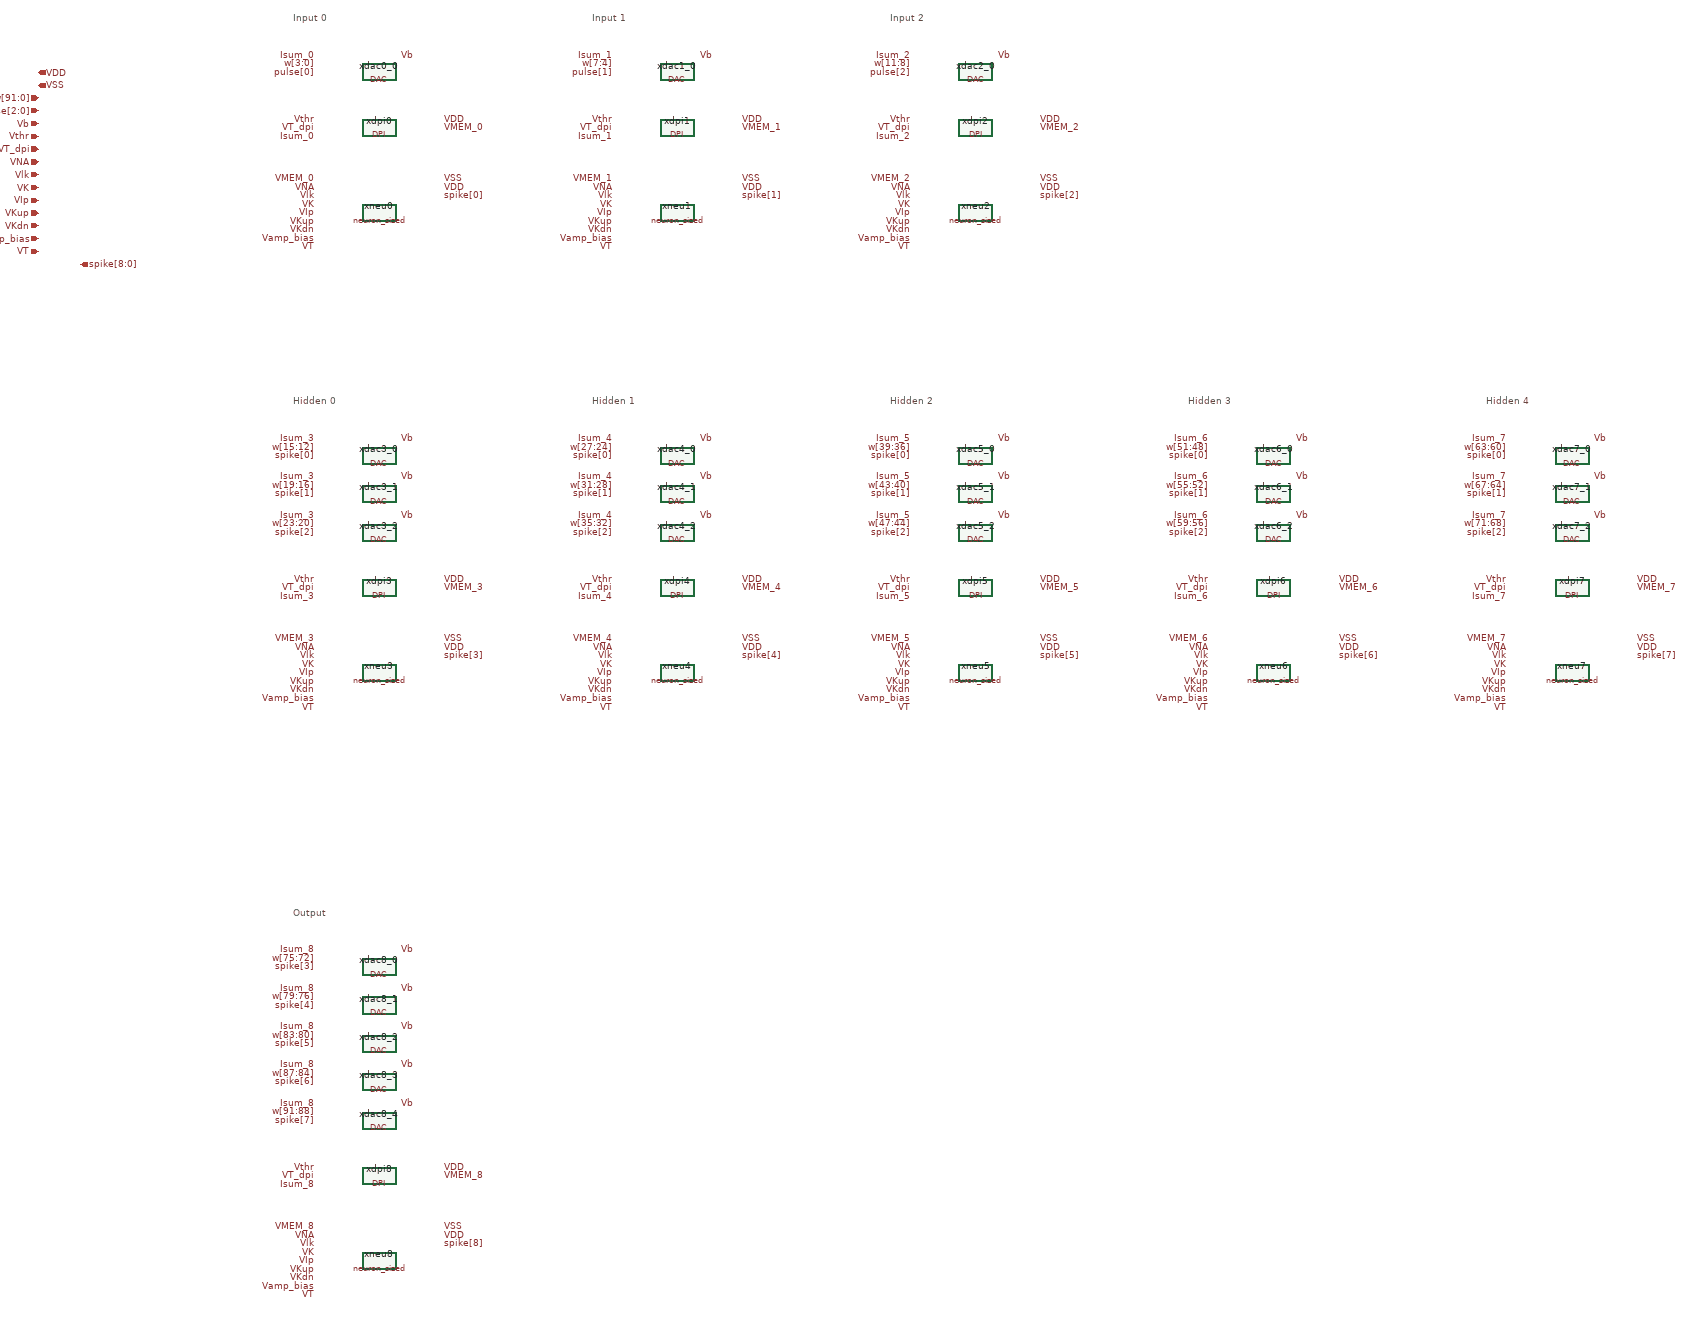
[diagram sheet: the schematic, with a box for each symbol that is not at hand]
v {xschem version=3.4.8RC file_version=1.3}
G {}
K {}
V {}
S {}
F {}
E {}
T {Input 0} 200 -1340 0 0 0.4 0.4 {}
C {DAC.sym} 400 -1200 0 0 {name=xdac0_0}
C {lab_pin.sym} 250 -1240 0 0 {name=l1 sig_type=std_logic lab=Isum_0}
C {lab_pin.sym} 450 -1240 0 1 {name=l2 sig_type=std_logic lab=Vb}
C {lab_pin.sym} 250 -1220 0 0 {name=l3 sig_type=std_logic lab=w[3:0]}
C {lab_pin.sym} 250 -1200 0 0 {name=l4 sig_type=std_logic lab=pulse[0]}
C {DPI.sym} 400 -1070 0 0 {name=xdpi0}
C {lab_pin.sym} 550 -1090 0 1 {name=l5 sig_type=std_logic lab=VDD}
C {lab_pin.sym} 250 -1090 0 0 {name=l6 sig_type=std_logic lab=Vthr}
C {lab_pin.sym} 550 -1070 0 1 {name=l7 sig_type=std_logic lab=VMEM_0}
C {lab_pin.sym} 250 -1050 0 0 {name=l8 sig_type=std_logic lab=Isum_0}
C {lab_pin.sym} 250 -1070 0 0 {name=l9 sig_type=std_logic lab=VT_dpi}
C {neuron_sized.sym} 400 -870 0 0 {name=xneu0}
C {lab_pin.sym} 550 -950 0 1 {name=l10 sig_type=std_logic lab=VSS}
C {lab_pin.sym} 550 -930 0 1 {name=l11 sig_type=std_logic lab=VDD}
C {lab_pin.sym} 550 -910 0 1 {name=l12 sig_type=std_logic lab=spike[0]}
C {lab_pin.sym} 250 -950 0 0 {name=l13 sig_type=std_logic lab=VMEM_0}
C {lab_pin.sym} 250 -930 0 0 {name=l14 sig_type=std_logic lab=VNA}
C {lab_pin.sym} 250 -910 0 0 {name=l15 sig_type=std_logic lab=Vlk}
C {lab_pin.sym} 250 -890 0 0 {name=l16 sig_type=std_logic lab=VK}
C {lab_pin.sym} 250 -870 0 0 {name=l17 sig_type=std_logic lab=VIp}
C {lab_pin.sym} 250 -850 0 0 {name=l18 sig_type=std_logic lab=VKup}
C {lab_pin.sym} 250 -830 0 0 {name=l19 sig_type=std_logic lab=VKdn}
C {lab_pin.sym} 250 -810 0 0 {name=l20 sig_type=std_logic lab=Vamp_bias}
C {lab_pin.sym} 250 -790 0 0 {name=l21 sig_type=std_logic lab=VT}
T {Input 1} 900 -1340 0 0 0.4 0.4 {}
C {DAC.sym} 1100 -1200 0 0 {name=xdac1_0}
C {lab_pin.sym} 950 -1240 0 0 {name=l22 sig_type=std_logic lab=Isum_1}
C {lab_pin.sym} 1150 -1240 0 1 {name=l23 sig_type=std_logic lab=Vb}
C {lab_pin.sym} 950 -1220 0 0 {name=l24 sig_type=std_logic lab=w[7:4]}
C {lab_pin.sym} 950 -1200 0 0 {name=l25 sig_type=std_logic lab=pulse[1]}
C {DPI.sym} 1100 -1070 0 0 {name=xdpi1}
C {lab_pin.sym} 1250 -1090 0 1 {name=l26 sig_type=std_logic lab=VDD}
C {lab_pin.sym} 950 -1090 0 0 {name=l27 sig_type=std_logic lab=Vthr}
C {lab_pin.sym} 1250 -1070 0 1 {name=l28 sig_type=std_logic lab=VMEM_1}
C {lab_pin.sym} 950 -1050 0 0 {name=l29 sig_type=std_logic lab=Isum_1}
C {lab_pin.sym} 950 -1070 0 0 {name=l30 sig_type=std_logic lab=VT_dpi}
C {neuron_sized.sym} 1100 -870 0 0 {name=xneu1}
C {lab_pin.sym} 1250 -950 0 1 {name=l31 sig_type=std_logic lab=VSS}
C {lab_pin.sym} 1250 -930 0 1 {name=l32 sig_type=std_logic lab=VDD}
C {lab_pin.sym} 1250 -910 0 1 {name=l33 sig_type=std_logic lab=spike[1]}
C {lab_pin.sym} 950 -950 0 0 {name=l34 sig_type=std_logic lab=VMEM_1}
C {lab_pin.sym} 950 -930 0 0 {name=l35 sig_type=std_logic lab=VNA}
C {lab_pin.sym} 950 -910 0 0 {name=l36 sig_type=std_logic lab=Vlk}
C {lab_pin.sym} 950 -890 0 0 {name=l37 sig_type=std_logic lab=VK}
C {lab_pin.sym} 950 -870 0 0 {name=l38 sig_type=std_logic lab=VIp}
C {lab_pin.sym} 950 -850 0 0 {name=l39 sig_type=std_logic lab=VKup}
C {lab_pin.sym} 950 -830 0 0 {name=l40 sig_type=std_logic lab=VKdn}
C {lab_pin.sym} 950 -810 0 0 {name=l41 sig_type=std_logic lab=Vamp_bias}
C {lab_pin.sym} 950 -790 0 0 {name=l42 sig_type=std_logic lab=VT}
T {Input 2} 1600 -1340 0 0 0.4 0.4 {}
C {DAC.sym} 1800 -1200 0 0 {name=xdac2_0}
C {lab_pin.sym} 1650 -1240 0 0 {name=l43 sig_type=std_logic lab=Isum_2}
C {lab_pin.sym} 1850 -1240 0 1 {name=l44 sig_type=std_logic lab=Vb}
C {lab_pin.sym} 1650 -1220 0 0 {name=l45 sig_type=std_logic lab=w[11:8]}
C {lab_pin.sym} 1650 -1200 0 0 {name=l46 sig_type=std_logic lab=pulse[2]}
C {DPI.sym} 1800 -1070 0 0 {name=xdpi2}
C {lab_pin.sym} 1950 -1090 0 1 {name=l47 sig_type=std_logic lab=VDD}
C {lab_pin.sym} 1650 -1090 0 0 {name=l48 sig_type=std_logic lab=Vthr}
C {lab_pin.sym} 1950 -1070 0 1 {name=l49 sig_type=std_logic lab=VMEM_2}
C {lab_pin.sym} 1650 -1050 0 0 {name=l50 sig_type=std_logic lab=Isum_2}
C {lab_pin.sym} 1650 -1070 0 0 {name=l51 sig_type=std_logic lab=VT_dpi}
C {neuron_sized.sym} 1800 -870 0 0 {name=xneu2}
C {lab_pin.sym} 1950 -950 0 1 {name=l52 sig_type=std_logic lab=VSS}
C {lab_pin.sym} 1950 -930 0 1 {name=l53 sig_type=std_logic lab=VDD}
C {lab_pin.sym} 1950 -910 0 1 {name=l54 sig_type=std_logic lab=spike[2]}
C {lab_pin.sym} 1650 -950 0 0 {name=l55 sig_type=std_logic lab=VMEM_2}
C {lab_pin.sym} 1650 -930 0 0 {name=l56 sig_type=std_logic lab=VNA}
C {lab_pin.sym} 1650 -910 0 0 {name=l57 sig_type=std_logic lab=Vlk}
C {lab_pin.sym} 1650 -890 0 0 {name=l58 sig_type=std_logic lab=VK}
C {lab_pin.sym} 1650 -870 0 0 {name=l59 sig_type=std_logic lab=VIp}
C {lab_pin.sym} 1650 -850 0 0 {name=l60 sig_type=std_logic lab=VKup}
C {lab_pin.sym} 1650 -830 0 0 {name=l61 sig_type=std_logic lab=VKdn}
C {lab_pin.sym} 1650 -810 0 0 {name=l62 sig_type=std_logic lab=Vamp_bias}
C {lab_pin.sym} 1650 -790 0 0 {name=l63 sig_type=std_logic lab=VT}
T {Hidden 0} 200 -440 0 0 0.4 0.4 {}
C {DAC.sym} 400 -300 0 0 {name=xdac3_0}
C {lab_pin.sym} 250 -340 0 0 {name=l64 sig_type=std_logic lab=Isum_3}
C {lab_pin.sym} 450 -340 0 1 {name=l65 sig_type=std_logic lab=Vb}
C {lab_pin.sym} 250 -320 0 0 {name=l66 sig_type=std_logic lab=w[15:12]}
C {lab_pin.sym} 250 -300 0 0 {name=l67 sig_type=std_logic lab=spike[0]}
C {DAC.sym} 400 -210 0 0 {name=xdac3_1}
C {lab_pin.sym} 250 -250 0 0 {name=l68 sig_type=std_logic lab=Isum_3}
C {lab_pin.sym} 450 -250 0 1 {name=l69 sig_type=std_logic lab=Vb}
C {lab_pin.sym} 250 -230 0 0 {name=l70 sig_type=std_logic lab=w[19:16]}
C {lab_pin.sym} 250 -210 0 0 {name=l71 sig_type=std_logic lab=spike[1]}
C {DAC.sym} 400 -120 0 0 {name=xdac3_2}
C {lab_pin.sym} 250 -160 0 0 {name=l72 sig_type=std_logic lab=Isum_3}
C {lab_pin.sym} 450 -160 0 1 {name=l73 sig_type=std_logic lab=Vb}
C {lab_pin.sym} 250 -140 0 0 {name=l74 sig_type=std_logic lab=w[23:20]}
C {lab_pin.sym} 250 -120 0 0 {name=l75 sig_type=std_logic lab=spike[2]}
C {DPI.sym} 400 10 0 0 {name=xdpi3}
C {lab_pin.sym} 550 -10 0 1 {name=l76 sig_type=std_logic lab=VDD}
C {lab_pin.sym} 250 -10 0 0 {name=l77 sig_type=std_logic lab=Vthr}
C {lab_pin.sym} 550 10 0 1 {name=l78 sig_type=std_logic lab=VMEM_3}
C {lab_pin.sym} 250 30 0 0 {name=l79 sig_type=std_logic lab=Isum_3}
C {lab_pin.sym} 250 10 0 0 {name=l80 sig_type=std_logic lab=VT_dpi}
C {neuron_sized.sym} 400 210 0 0 {name=xneu3}
C {lab_pin.sym} 550 130 0 1 {name=l81 sig_type=std_logic lab=VSS}
C {lab_pin.sym} 550 150 0 1 {name=l82 sig_type=std_logic lab=VDD}
C {lab_pin.sym} 550 170 0 1 {name=l83 sig_type=std_logic lab=spike[3]}
C {lab_pin.sym} 250 130 0 0 {name=l84 sig_type=std_logic lab=VMEM_3}
C {lab_pin.sym} 250 150 0 0 {name=l85 sig_type=std_logic lab=VNA}
C {lab_pin.sym} 250 170 0 0 {name=l86 sig_type=std_logic lab=Vlk}
C {lab_pin.sym} 250 190 0 0 {name=l87 sig_type=std_logic lab=VK}
C {lab_pin.sym} 250 210 0 0 {name=l88 sig_type=std_logic lab=VIp}
C {lab_pin.sym} 250 230 0 0 {name=l89 sig_type=std_logic lab=VKup}
C {lab_pin.sym} 250 250 0 0 {name=l90 sig_type=std_logic lab=VKdn}
C {lab_pin.sym} 250 270 0 0 {name=l91 sig_type=std_logic lab=Vamp_bias}
C {lab_pin.sym} 250 290 0 0 {name=l92 sig_type=std_logic lab=VT}
T {Hidden 1} 900 -440 0 0 0.4 0.4 {}
C {DAC.sym} 1100 -300 0 0 {name=xdac4_0}
C {lab_pin.sym} 950 -340 0 0 {name=l93 sig_type=std_logic lab=Isum_4}
C {lab_pin.sym} 1150 -340 0 1 {name=l94 sig_type=std_logic lab=Vb}
C {lab_pin.sym} 950 -320 0 0 {name=l95 sig_type=std_logic lab=w[27:24]}
C {lab_pin.sym} 950 -300 0 0 {name=l96 sig_type=std_logic lab=spike[0]}
C {DAC.sym} 1100 -210 0 0 {name=xdac4_1}
C {lab_pin.sym} 950 -250 0 0 {name=l97 sig_type=std_logic lab=Isum_4}
C {lab_pin.sym} 1150 -250 0 1 {name=l98 sig_type=std_logic lab=Vb}
C {lab_pin.sym} 950 -230 0 0 {name=l99 sig_type=std_logic lab=w[31:28]}
C {lab_pin.sym} 950 -210 0 0 {name=l100 sig_type=std_logic lab=spike[1]}
C {DAC.sym} 1100 -120 0 0 {name=xdac4_2}
C {lab_pin.sym} 950 -160 0 0 {name=l101 sig_type=std_logic lab=Isum_4}
C {lab_pin.sym} 1150 -160 0 1 {name=l102 sig_type=std_logic lab=Vb}
C {lab_pin.sym} 950 -140 0 0 {name=l103 sig_type=std_logic lab=w[35:32]}
C {lab_pin.sym} 950 -120 0 0 {name=l104 sig_type=std_logic lab=spike[2]}
C {DPI.sym} 1100 10 0 0 {name=xdpi4}
C {lab_pin.sym} 1250 -10 0 1 {name=l105 sig_type=std_logic lab=VDD}
C {lab_pin.sym} 950 -10 0 0 {name=l106 sig_type=std_logic lab=Vthr}
C {lab_pin.sym} 1250 10 0 1 {name=l107 sig_type=std_logic lab=VMEM_4}
C {lab_pin.sym} 950 30 0 0 {name=l108 sig_type=std_logic lab=Isum_4}
C {lab_pin.sym} 950 10 0 0 {name=l109 sig_type=std_logic lab=VT_dpi}
C {neuron_sized.sym} 1100 210 0 0 {name=xneu4}
C {lab_pin.sym} 1250 130 0 1 {name=l110 sig_type=std_logic lab=VSS}
C {lab_pin.sym} 1250 150 0 1 {name=l111 sig_type=std_logic lab=VDD}
C {lab_pin.sym} 1250 170 0 1 {name=l112 sig_type=std_logic lab=spike[4]}
C {lab_pin.sym} 950 130 0 0 {name=l113 sig_type=std_logic lab=VMEM_4}
C {lab_pin.sym} 950 150 0 0 {name=l114 sig_type=std_logic lab=VNA}
C {lab_pin.sym} 950 170 0 0 {name=l115 sig_type=std_logic lab=Vlk}
C {lab_pin.sym} 950 190 0 0 {name=l116 sig_type=std_logic lab=VK}
C {lab_pin.sym} 950 210 0 0 {name=l117 sig_type=std_logic lab=VIp}
C {lab_pin.sym} 950 230 0 0 {name=l118 sig_type=std_logic lab=VKup}
C {lab_pin.sym} 950 250 0 0 {name=l119 sig_type=std_logic lab=VKdn}
C {lab_pin.sym} 950 270 0 0 {name=l120 sig_type=std_logic lab=Vamp_bias}
C {lab_pin.sym} 950 290 0 0 {name=l121 sig_type=std_logic lab=VT}
T {Hidden 2} 1600 -440 0 0 0.4 0.4 {}
C {DAC.sym} 1800 -300 0 0 {name=xdac5_0}
C {lab_pin.sym} 1650 -340 0 0 {name=l122 sig_type=std_logic lab=Isum_5}
C {lab_pin.sym} 1850 -340 0 1 {name=l123 sig_type=std_logic lab=Vb}
C {lab_pin.sym} 1650 -320 0 0 {name=l124 sig_type=std_logic lab=w[39:36]}
C {lab_pin.sym} 1650 -300 0 0 {name=l125 sig_type=std_logic lab=spike[0]}
C {DAC.sym} 1800 -210 0 0 {name=xdac5_1}
C {lab_pin.sym} 1650 -250 0 0 {name=l126 sig_type=std_logic lab=Isum_5}
C {lab_pin.sym} 1850 -250 0 1 {name=l127 sig_type=std_logic lab=Vb}
C {lab_pin.sym} 1650 -230 0 0 {name=l128 sig_type=std_logic lab=w[43:40]}
C {lab_pin.sym} 1650 -210 0 0 {name=l129 sig_type=std_logic lab=spike[1]}
C {DAC.sym} 1800 -120 0 0 {name=xdac5_2}
C {lab_pin.sym} 1650 -160 0 0 {name=l130 sig_type=std_logic lab=Isum_5}
C {lab_pin.sym} 1850 -160 0 1 {name=l131 sig_type=std_logic lab=Vb}
C {lab_pin.sym} 1650 -140 0 0 {name=l132 sig_type=std_logic lab=w[47:44]}
C {lab_pin.sym} 1650 -120 0 0 {name=l133 sig_type=std_logic lab=spike[2]}
C {DPI.sym} 1800 10 0 0 {name=xdpi5}
C {lab_pin.sym} 1950 -10 0 1 {name=l134 sig_type=std_logic lab=VDD}
C {lab_pin.sym} 1650 -10 0 0 {name=l135 sig_type=std_logic lab=Vthr}
C {lab_pin.sym} 1950 10 0 1 {name=l136 sig_type=std_logic lab=VMEM_5}
C {lab_pin.sym} 1650 30 0 0 {name=l137 sig_type=std_logic lab=Isum_5}
C {lab_pin.sym} 1650 10 0 0 {name=l138 sig_type=std_logic lab=VT_dpi}
C {neuron_sized.sym} 1800 210 0 0 {name=xneu5}
C {lab_pin.sym} 1950 130 0 1 {name=l139 sig_type=std_logic lab=VSS}
C {lab_pin.sym} 1950 150 0 1 {name=l140 sig_type=std_logic lab=VDD}
C {lab_pin.sym} 1950 170 0 1 {name=l141 sig_type=std_logic lab=spike[5]}
C {lab_pin.sym} 1650 130 0 0 {name=l142 sig_type=std_logic lab=VMEM_5}
C {lab_pin.sym} 1650 150 0 0 {name=l143 sig_type=std_logic lab=VNA}
C {lab_pin.sym} 1650 170 0 0 {name=l144 sig_type=std_logic lab=Vlk}
C {lab_pin.sym} 1650 190 0 0 {name=l145 sig_type=std_logic lab=VK}
C {lab_pin.sym} 1650 210 0 0 {name=l146 sig_type=std_logic lab=VIp}
C {lab_pin.sym} 1650 230 0 0 {name=l147 sig_type=std_logic lab=VKup}
C {lab_pin.sym} 1650 250 0 0 {name=l148 sig_type=std_logic lab=VKdn}
C {lab_pin.sym} 1650 270 0 0 {name=l149 sig_type=std_logic lab=Vamp_bias}
C {lab_pin.sym} 1650 290 0 0 {name=l150 sig_type=std_logic lab=VT}
T {Hidden 3} 2300 -440 0 0 0.4 0.4 {}
C {DAC.sym} 2500 -300 0 0 {name=xdac6_0}
C {lab_pin.sym} 2350 -340 0 0 {name=l151 sig_type=std_logic lab=Isum_6}
C {lab_pin.sym} 2550 -340 0 1 {name=l152 sig_type=std_logic lab=Vb}
C {lab_pin.sym} 2350 -320 0 0 {name=l153 sig_type=std_logic lab=w[51:48]}
C {lab_pin.sym} 2350 -300 0 0 {name=l154 sig_type=std_logic lab=spike[0]}
C {DAC.sym} 2500 -210 0 0 {name=xdac6_1}
C {lab_pin.sym} 2350 -250 0 0 {name=l155 sig_type=std_logic lab=Isum_6}
C {lab_pin.sym} 2550 -250 0 1 {name=l156 sig_type=std_logic lab=Vb}
C {lab_pin.sym} 2350 -230 0 0 {name=l157 sig_type=std_logic lab=w[55:52]}
C {lab_pin.sym} 2350 -210 0 0 {name=l158 sig_type=std_logic lab=spike[1]}
C {DAC.sym} 2500 -120 0 0 {name=xdac6_2}
C {lab_pin.sym} 2350 -160 0 0 {name=l159 sig_type=std_logic lab=Isum_6}
C {lab_pin.sym} 2550 -160 0 1 {name=l160 sig_type=std_logic lab=Vb}
C {lab_pin.sym} 2350 -140 0 0 {name=l161 sig_type=std_logic lab=w[59:56]}
C {lab_pin.sym} 2350 -120 0 0 {name=l162 sig_type=std_logic lab=spike[2]}
C {DPI.sym} 2500 10 0 0 {name=xdpi6}
C {lab_pin.sym} 2650 -10 0 1 {name=l163 sig_type=std_logic lab=VDD}
C {lab_pin.sym} 2350 -10 0 0 {name=l164 sig_type=std_logic lab=Vthr}
C {lab_pin.sym} 2650 10 0 1 {name=l165 sig_type=std_logic lab=VMEM_6}
C {lab_pin.sym} 2350 30 0 0 {name=l166 sig_type=std_logic lab=Isum_6}
C {lab_pin.sym} 2350 10 0 0 {name=l167 sig_type=std_logic lab=VT_dpi}
C {neuron_sized.sym} 2500 210 0 0 {name=xneu6}
C {lab_pin.sym} 2650 130 0 1 {name=l168 sig_type=std_logic lab=VSS}
C {lab_pin.sym} 2650 150 0 1 {name=l169 sig_type=std_logic lab=VDD}
C {lab_pin.sym} 2650 170 0 1 {name=l170 sig_type=std_logic lab=spike[6]}
C {lab_pin.sym} 2350 130 0 0 {name=l171 sig_type=std_logic lab=VMEM_6}
C {lab_pin.sym} 2350 150 0 0 {name=l172 sig_type=std_logic lab=VNA}
C {lab_pin.sym} 2350 170 0 0 {name=l173 sig_type=std_logic lab=Vlk}
C {lab_pin.sym} 2350 190 0 0 {name=l174 sig_type=std_logic lab=VK}
C {lab_pin.sym} 2350 210 0 0 {name=l175 sig_type=std_logic lab=VIp}
C {lab_pin.sym} 2350 230 0 0 {name=l176 sig_type=std_logic lab=VKup}
C {lab_pin.sym} 2350 250 0 0 {name=l177 sig_type=std_logic lab=VKdn}
C {lab_pin.sym} 2350 270 0 0 {name=l178 sig_type=std_logic lab=Vamp_bias}
C {lab_pin.sym} 2350 290 0 0 {name=l179 sig_type=std_logic lab=VT}
T {Hidden 4} 3000 -440 0 0 0.4 0.4 {}
C {DAC.sym} 3200 -300 0 0 {name=xdac7_0}
C {lab_pin.sym} 3050 -340 0 0 {name=l180 sig_type=std_logic lab=Isum_7}
C {lab_pin.sym} 3250 -340 0 1 {name=l181 sig_type=std_logic lab=Vb}
C {lab_pin.sym} 3050 -320 0 0 {name=l182 sig_type=std_logic lab=w[63:60]}
C {lab_pin.sym} 3050 -300 0 0 {name=l183 sig_type=std_logic lab=spike[0]}
C {DAC.sym} 3200 -210 0 0 {name=xdac7_1}
C {lab_pin.sym} 3050 -250 0 0 {name=l184 sig_type=std_logic lab=Isum_7}
C {lab_pin.sym} 3250 -250 0 1 {name=l185 sig_type=std_logic lab=Vb}
C {lab_pin.sym} 3050 -230 0 0 {name=l186 sig_type=std_logic lab=w[67:64]}
C {lab_pin.sym} 3050 -210 0 0 {name=l187 sig_type=std_logic lab=spike[1]}
C {DAC.sym} 3200 -120 0 0 {name=xdac7_2}
C {lab_pin.sym} 3050 -160 0 0 {name=l188 sig_type=std_logic lab=Isum_7}
C {lab_pin.sym} 3250 -160 0 1 {name=l189 sig_type=std_logic lab=Vb}
C {lab_pin.sym} 3050 -140 0 0 {name=l190 sig_type=std_logic lab=w[71:68]}
C {lab_pin.sym} 3050 -120 0 0 {name=l191 sig_type=std_logic lab=spike[2]}
C {DPI.sym} 3200 10 0 0 {name=xdpi7}
C {lab_pin.sym} 3350 -10 0 1 {name=l192 sig_type=std_logic lab=VDD}
C {lab_pin.sym} 3050 -10 0 0 {name=l193 sig_type=std_logic lab=Vthr}
C {lab_pin.sym} 3350 10 0 1 {name=l194 sig_type=std_logic lab=VMEM_7}
C {lab_pin.sym} 3050 30 0 0 {name=l195 sig_type=std_logic lab=Isum_7}
C {lab_pin.sym} 3050 10 0 0 {name=l196 sig_type=std_logic lab=VT_dpi}
C {neuron_sized.sym} 3200 210 0 0 {name=xneu7}
C {lab_pin.sym} 3350 130 0 1 {name=l197 sig_type=std_logic lab=VSS}
C {lab_pin.sym} 3350 150 0 1 {name=l198 sig_type=std_logic lab=VDD}
C {lab_pin.sym} 3350 170 0 1 {name=l199 sig_type=std_logic lab=spike[7]}
C {lab_pin.sym} 3050 130 0 0 {name=l200 sig_type=std_logic lab=VMEM_7}
C {lab_pin.sym} 3050 150 0 0 {name=l201 sig_type=std_logic lab=VNA}
C {lab_pin.sym} 3050 170 0 0 {name=l202 sig_type=std_logic lab=Vlk}
C {lab_pin.sym} 3050 190 0 0 {name=l203 sig_type=std_logic lab=VK}
C {lab_pin.sym} 3050 210 0 0 {name=l204 sig_type=std_logic lab=VIp}
C {lab_pin.sym} 3050 230 0 0 {name=l205 sig_type=std_logic lab=VKup}
C {lab_pin.sym} 3050 250 0 0 {name=l206 sig_type=std_logic lab=VKdn}
C {lab_pin.sym} 3050 270 0 0 {name=l207 sig_type=std_logic lab=Vamp_bias}
C {lab_pin.sym} 3050 290 0 0 {name=l208 sig_type=std_logic lab=VT}
T {Output} 200 760 0 0 0.4 0.4 {}
C {DAC.sym} 400 900 0 0 {name=xdac8_0}
C {lab_pin.sym} 250 860 0 0 {name=l209 sig_type=std_logic lab=Isum_8}
C {lab_pin.sym} 450 860 0 1 {name=l210 sig_type=std_logic lab=Vb}
C {lab_pin.sym} 250 880 0 0 {name=l211 sig_type=std_logic lab=w[75:72]}
C {lab_pin.sym} 250 900 0 0 {name=l212 sig_type=std_logic lab=spike[3]}
C {DAC.sym} 400 990 0 0 {name=xdac8_1}
C {lab_pin.sym} 250 950 0 0 {name=l213 sig_type=std_logic lab=Isum_8}
C {lab_pin.sym} 450 950 0 1 {name=l214 sig_type=std_logic lab=Vb}
C {lab_pin.sym} 250 970 0 0 {name=l215 sig_type=std_logic lab=w[79:76]}
C {lab_pin.sym} 250 990 0 0 {name=l216 sig_type=std_logic lab=spike[4]}
C {DAC.sym} 400 1080 0 0 {name=xdac8_2}
C {lab_pin.sym} 250 1040 0 0 {name=l217 sig_type=std_logic lab=Isum_8}
C {lab_pin.sym} 450 1040 0 1 {name=l218 sig_type=std_logic lab=Vb}
C {lab_pin.sym} 250 1060 0 0 {name=l219 sig_type=std_logic lab=w[83:80]}
C {lab_pin.sym} 250 1080 0 0 {name=l220 sig_type=std_logic lab=spike[5]}
C {DAC.sym} 400 1170 0 0 {name=xdac8_3}
C {lab_pin.sym} 250 1130 0 0 {name=l221 sig_type=std_logic lab=Isum_8}
C {lab_pin.sym} 450 1130 0 1 {name=l222 sig_type=std_logic lab=Vb}
C {lab_pin.sym} 250 1150 0 0 {name=l223 sig_type=std_logic lab=w[87:84]}
C {lab_pin.sym} 250 1170 0 0 {name=l224 sig_type=std_logic lab=spike[6]}
C {DAC.sym} 400 1260 0 0 {name=xdac8_4}
C {lab_pin.sym} 250 1220 0 0 {name=l225 sig_type=std_logic lab=Isum_8}
C {lab_pin.sym} 450 1220 0 1 {name=l226 sig_type=std_logic lab=Vb}
C {lab_pin.sym} 250 1240 0 0 {name=l227 sig_type=std_logic lab=w[91:88]}
C {lab_pin.sym} 250 1260 0 0 {name=l228 sig_type=std_logic lab=spike[7]}
C {DPI.sym} 400 1390 0 0 {name=xdpi8}
C {lab_pin.sym} 550 1370 0 1 {name=l229 sig_type=std_logic lab=VDD}
C {lab_pin.sym} 250 1370 0 0 {name=l230 sig_type=std_logic lab=Vthr}
C {lab_pin.sym} 550 1390 0 1 {name=l231 sig_type=std_logic lab=VMEM_8}
C {lab_pin.sym} 250 1410 0 0 {name=l232 sig_type=std_logic lab=Isum_8}
C {lab_pin.sym} 250 1390 0 0 {name=l233 sig_type=std_logic lab=VT_dpi}
C {neuron_sized.sym} 400 1590 0 0 {name=xneu8}
C {lab_pin.sym} 550 1510 0 1 {name=l234 sig_type=std_logic lab=VSS}
C {lab_pin.sym} 550 1530 0 1 {name=l235 sig_type=std_logic lab=VDD}
C {lab_pin.sym} 550 1550 0 1 {name=l236 sig_type=std_logic lab=spike[8]}
C {lab_pin.sym} 250 1510 0 0 {name=l237 sig_type=std_logic lab=VMEM_8}
C {lab_pin.sym} 250 1530 0 0 {name=l238 sig_type=std_logic lab=VNA}
C {lab_pin.sym} 250 1550 0 0 {name=l239 sig_type=std_logic lab=Vlk}
C {lab_pin.sym} 250 1570 0 0 {name=l240 sig_type=std_logic lab=VK}
C {lab_pin.sym} 250 1590 0 0 {name=l241 sig_type=std_logic lab=VIp}
C {lab_pin.sym} 250 1610 0 0 {name=l242 sig_type=std_logic lab=VKup}
C {lab_pin.sym} 250 1630 0 0 {name=l243 sig_type=std_logic lab=VKdn}
C {lab_pin.sym} 250 1650 0 0 {name=l244 sig_type=std_logic lab=Vamp_bias}
C {lab_pin.sym} 250 1670 0 0 {name=l245 sig_type=std_logic lab=VT}
C {iopin.sym} -400 -1200 0 1 {name=p_VDD lab=VDD}
C {iopin.sym} -400 -1170 0 1 {name=p_VSS lab=VSS}
C {ipin.sym} -400 -1140 0 0 {name=p_w lab=w[91:0]}
C {ipin.sym} -400 -1110 0 0 {name=p_pulse lab=pulse[2:0]}
C {ipin.sym} -400 -1080 0 0 {name=p_Vb lab=Vb}
C {ipin.sym} -400 -1050 0 0 {name=p_Vthr lab=Vthr}
C {ipin.sym} -400 -1020 0 0 {name=p_VT_dpi lab=VT_dpi}
C {ipin.sym} -400 -990 0 0 {name=p_VNA lab=VNA}
C {ipin.sym} -400 -960 0 0 {name=p_Vlk lab=Vlk}
C {ipin.sym} -400 -930 0 0 {name=p_VK lab=VK}
C {ipin.sym} -400 -900 0 0 {name=p_VIp lab=VIp}
C {ipin.sym} -400 -870 0 0 {name=p_VKup lab=VKup}
C {ipin.sym} -400 -840 0 0 {name=p_VKdn lab=VKdn}
C {ipin.sym} -400 -810 0 0 {name=p_Vamp_bias lab=Vamp_bias}
C {ipin.sym} -400 -780 0 0 {name=p_VT lab=VT}
C {opin.sym} -300 -750 0 0 {name=p_spike lab=spike[8:0]}
T {snn_analog: the 3-5-1 network of mock/snn_analog.v built from DAC -> DPI -> neuron_sized.
Word k of w is synapse k (4 bits, w[4k+3:4k]): words 0-2 pulse[i] -> input i, 3-17 input i -> hidden j (3 + 3j + i),
18-22 hidden j -> output (18 + j). spike = {output, hidden[4:0], input[2:0]}.
Each neuron's DACs share one DPI (Isum_n); the DPI output drives the membrane VMEM_n.
Generated by a script; edit freely.} -400 -1500 0 0 0.4 0.4 {}
